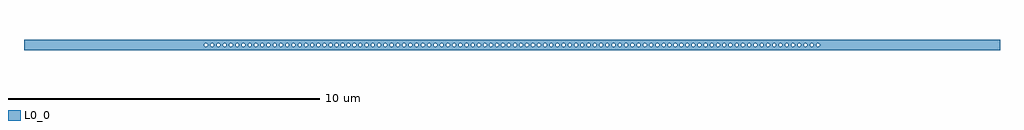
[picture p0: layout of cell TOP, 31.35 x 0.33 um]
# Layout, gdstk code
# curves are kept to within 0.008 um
import gdstk
lib = gdstk.Library(unit=1e-6, precision=1e-09)
def P(c, l, *ps):  # polygons
    for p in ps: c.add(gdstk.Polygon(p, *l))
L0_0 = (0, 0)

top = lib.new_cell('TOP')
P(top, L0_0, [(0,0),(0,0),(0,0),(0,0)],
  [(-8.009,0.053),(-8.009,0.166),(-15.675,0.166),(-15.675,0.055),(-8.027,0.055)],
  [(-8.009,-0.053),(-8.045,-0.051),(-8.077,-0.009),(-8.071,0.026),(-8.027,0.055),(-8.228,0.055),(-8.18,0.034),(-8.168,0),(-8.18,-0.034),(-8.228,-0.055),(-8.26,-0.041),(-8.278,-0.009),(-8.272,0.026),(-8.228,0.055),(-8.429,0.055),(-8.381,0.034),(-8.369,0),(-8.381,-0.034),(-8.429,-0.055),(-8.461,-0.041),(-8.479,-0.009),(-8.473,0.026),(-8.429,0.055),(-8.63,0.055),(-8.582,0.034),(-8.57,0),(-8.582,-0.034),(-8.63,-0.055),(-8.662,-0.041),(-8.68,-0.009),(-8.674,0.026),(-8.63,0.055),(-8.831,0.055),(-8.783,0.034),(-8.771,0),(-8.783,-0.034),(-8.831,-0.055),(-8.863,-0.041),(-8.881,-0.009),(-8.875,0.026),(-8.831,0.055),(-9.032,0.055),(-8.984,0.034),(-8.972,0),(-8.984,-0.034),(-9.032,-0.055),(-9.064,-0.041),(-9.082,-0.009),(-9.076,0.026),(-9.032,0.055),(-9.233,0.055),(-9.185,0.034),(-9.173,0),(-9.185,-0.034),(-9.233,-0.055),(-9.265,-0.041),(-9.283,-0.009),(-9.277,0.026),(-9.233,0.055),(-9.434,0.055),(-9.386,0.034),(-9.374,0),(-9.386,-0.034),(-9.434,-0.055),(-9.466,-0.041),(-9.484,-0.009),(-9.478,0.026),(-9.434,0.055),(-9.635,0.055),(-9.587,0.034),(-9.575,0),(-9.587,-0.034),(-9.635,-0.055),(-9.667,-0.041),(-9.685,-0.009),(-9.679,0.026),(-9.635,0.055),(-9.836,0.055),(-9.788,0.034),(-9.776,0),(-9.788,-0.034),(-9.836,-0.055),(-9.868,-0.041),(-9.886,-0.009),(-9.88,0.026),(-9.836,0.055),(-15.675,0.055),(-15.675,-0.166),(-8.009,-0.166)],
  [(-6.206,0.053),(-6.189,0.046),(-6.176,0.034),(-6.167,0.018),(-6.167,0.166),(-8.009,0.166),(-8.009,0.055),(-6.224,0.055)],
  [(-6.167,-0.018),(-6.189,-0.046),(-6.224,-0.055),(-6.268,-0.026),(-6.268,0.026),(-6.224,0.055),(-6.422,0.055),(-6.375,0.034),(-6.363,0),(-6.375,-0.034),(-6.422,-0.055),(-6.455,-0.041),(-6.472,-0.009),(-6.455,0.041),(-6.422,0.055),(-6.622,0.055),(-6.587,0.046),(-6.562,0),(-6.587,-0.046),(-6.622,-0.055),(-6.654,-0.041),(-6.671,-0.009),(-6.654,0.041),(-6.622,0.055),(-6.822,0.055),(-6.787,0.046),(-6.762,0),(-6.787,-0.046),(-6.822,-0.055),(-6.854,-0.041),(-6.871,-0.009),(-6.866,0.026),(-6.822,0.055),(-7.022,0.055),(-6.975,0.034),(-6.963,0),(-6.975,-0.034),(-7.022,-0.055),(-7.055,-0.041),(-7.072,-0.009),(-7.055,0.041),(-7.022,0.055),(-7.223,0.055),(-7.175,0.034),(-7.164,0),(-7.175,-0.034),(-7.223,-0.055),(-7.256,-0.041),(-7.273,-0.009),(-7.256,0.041),(-7.223,0.055),(-7.424,0.055),(-7.376,0.034),(-7.365,0),(-7.376,-0.034),(-7.424,-0.055),(-7.457,-0.041),(-7.474,-0.009),(-7.457,0.041),(-7.424,0.055),(-7.625,0.055),(-7.577,0.034),(-7.565,0),(-7.577,-0.034),(-7.625,-0.055),(-7.657,-0.041),(-7.675,-0.009),(-7.669,0.026),(-7.625,0.055),(-7.826,0.055),(-7.778,0.034),(-7.766,0),(-7.778,-0.034),(-7.826,-0.055),(-7.858,-0.041),(-7.876,-0.009),(-7.87,0.026),(-7.826,0.055),(-8.009,0.055),(-7.979,0.034),(-7.967,0),(-7.979,-0.034),(-8.009,-0.053),(-8.009,-0.166),(-6.167,-0.166)],
  [(-4.457,0.053),(-4.44,0.046),(-4.427,0.034),(-4.418,0.018),(-4.418,0.166),(-6.167,0.166),(-6.167,0.055),(-4.474,0.055)],
  [(-4.418,-0.018),(-4.457,-0.053),(-4.507,-0.041),(-4.524,0.009),(-4.507,0.041),(-4.474,0.055),(-4.675,0.055),(-4.628,0.034),(-4.616,0),(-4.628,-0.034),(-4.675,-0.055),(-4.708,-0.041),(-4.725,-0.009),(-4.708,0.041),(-4.675,0.055),(-4.876,0.055),(-4.829,0.034),(-4.817,0),(-4.829,-0.034),(-4.876,-0.055),(-4.909,-0.041),(-4.926,-0.009),(-4.909,0.041),(-4.876,0.055),(-5.065,0.055),(-5.018,0.034),(-5.006,0),(-5.018,-0.034),(-5.065,-0.055),(-5.098,-0.041),(-5.115,-0.009),(-5.098,0.041),(-5.065,0.055),(-5.255,0.055),(-5.22,0.046),(-5.195,0),(-5.22,-0.046),(-5.255,-0.055),(-5.287,-0.041),(-5.304,-0.009),(-5.299,0.026),(-5.255,0.055),(-5.445,0.055),(-5.397,0.034),(-5.386,0),(-5.397,-0.034),(-5.445,-0.055),(-5.478,-0.041),(-5.495,-0.009),(-5.478,0.041),(-5.445,0.055),(-5.637,0.055),(-5.589,0.034),(-5.578,0),(-5.589,-0.034),(-5.637,-0.055),(-5.67,-0.041),(-5.687,-0.009),(-5.67,0.041),(-5.637,0.055),(-5.831,0.055),(-5.783,0.034),(-5.772,0),(-5.783,-0.034),(-5.831,-0.055),(-5.864,-0.041),(-5.881,-0.009),(-5.864,0.041),(-5.831,0.055),(-6.027,0.055),(-5.992,0.046),(-5.967,0),(-5.992,-0.046),(-6.027,-0.055),(-6.059,-0.041),(-6.076,-0.009),(-6.059,0.041),(-6.027,0.055),(-6.167,0.055),(-6.167,-0.166),(-4.418,-0.166)],
  [(-2.648,0.053),(-2.631,0.046),(-2.618,0.034),(-2.609,0.018),(-2.609,0.166),(-4.418,0.166),(-4.418,0.055),(-2.665,0.055)],
  [(-2.609,-0.018),(-2.648,-0.053),(-2.698,-0.041),(-2.715,0.009),(-2.698,0.041),(-2.665,0.055),(-2.866,0.055),(-2.819,0.034),(-2.807,0),(-2.819,-0.034),(-2.866,-0.055),(-2.899,-0.041),(-2.916,-0.009),(-2.899,0.041),(-2.866,0.055),(-3.067,0.055),(-3.02,0.034),(-3.008,0),(-3.02,-0.034),(-3.067,-0.055),(-3.1,-0.041),(-3.117,-0.009),(-3.1,0.041),(-3.067,0.055),(-3.268,0.055),(-3.221,0.034),(-3.209,0),(-3.221,-0.034),(-3.268,-0.055),(-3.301,-0.041),(-3.318,-0.009),(-3.301,0.041),(-3.268,0.055),(-3.469,0.055),(-3.422,0.034),(-3.41,0),(-3.422,-0.034),(-3.469,-0.055),(-3.502,-0.041),(-3.519,-0.009),(-3.502,0.041),(-3.469,0.055),(-3.67,0.055),(-3.623,0.034),(-3.611,0),(-3.623,-0.034),(-3.67,-0.055),(-3.703,-0.041),(-3.72,-0.009),(-3.703,0.041),(-3.67,0.055),(-3.871,0.055),(-3.824,0.034),(-3.812,0),(-3.824,-0.034),(-3.871,-0.055),(-3.904,-0.041),(-3.921,-0.009),(-3.904,0.041),(-3.871,0.055),(-4.072,0.055),(-4.025,0.034),(-4.013,0),(-4.025,-0.034),(-4.072,-0.055),(-4.105,-0.041),(-4.122,-0.009),(-4.105,0.041),(-4.072,0.055),(-4.273,0.055),(-4.226,0.034),(-4.214,0),(-4.226,-0.034),(-4.273,-0.055),(-4.306,-0.041),(-4.323,-0.009),(-4.306,0.041),(-4.273,0.055),(-4.418,0.055),(-4.418,-0.166),(-2.609,-0.166)],
  [(-0.854,0.053),(-0.837,0.046),(-0.824,0.034),(-0.815,0.018),(-0.815,0.166),(-2.609,0.166),(-2.609,0.055),(-0.871,0.055)],
  [(-0.815,-0.018),(-0.854,-0.053),(-0.904,-0.041),(-0.921,0.009),(-0.904,0.041),(-0.871,0.055),(-1.067,0.055),(-1.019,0.034),(-1.008,0),(-1.019,-0.034),(-1.067,-0.055),(-1.1,-0.041),(-1.117,-0.009),(-1.1,0.041),(-1.067,0.055),(-1.264,0.055),(-1.217,0.034),(-1.205,0),(-1.217,-0.034),(-1.264,-0.055),(-1.297,-0.041),(-1.314,-0.009),(-1.297,0.041),(-1.264,0.055),(-1.463,0.055),(-1.428,0.046),(-1.403,0),(-1.428,-0.046),(-1.463,-0.055),(-1.495,-0.041),(-1.512,-0.009),(-1.507,0.026),(-1.463,0.055),(-1.662,0.055),(-1.615,0.034),(-1.603,0),(-1.615,-0.034),(-1.662,-0.055),(-1.695,-0.041),(-1.712,-0.009),(-1.695,0.041),(-1.662,0.055),(-1.862,0.055),(-1.815,0.034),(-1.803,0),(-1.815,-0.034),(-1.862,-0.055),(-1.895,-0.041),(-1.912,-0.009),(-1.895,0.041),(-1.862,0.055),(-2.063,0.055),(-2.015,0.034),(-2.003,0),(-2.015,-0.034),(-2.063,-0.055),(-2.095,-0.041),(-2.113,-0.009),(-2.107,0.026),(-2.063,0.055),(-2.264,0.055),(-2.229,0.046),(-2.204,0),(-2.229,-0.046),(-2.264,-0.055),(-2.296,-0.041),(-2.313,-0.009),(-2.296,0.041),(-2.264,0.055),(-2.464,0.055),(-2.417,0.034),(-2.405,0),(-2.417,-0.034),(-2.464,-0.055),(-2.497,-0.041),(-2.514,-0.009),(-2.497,0.041),(-2.464,0.055),(-2.609,0.055),(-2.609,-0.166),(-0.815,-0.166)],
  [(0.881,0.053),(0.897,0.046),(0.91,0.034),(0.919,0.018),(0.919,0.166),(-0.815,0.166),(-0.815,0.055),(0.863,0.055)],
  [(0.919,-0.018),(0.881,-0.053),(0.83,-0.041),(0.813,0.009),(0.83,0.041),(0.863,0.055),(0.669,0.055),(0.717,0.034),(0.728,0),(0.717,-0.034),(0.669,-0.055),(0.636,-0.041),(0.619,-0.009),(0.636,0.041),(0.669,0.055),(0.477,0.055),(0.525,0.034),(0.536,0),(0.525,-0.034),(0.477,-0.055),(0.444,-0.041),(0.427,-0.009),(0.444,0.041),(0.477,0.055),(0.287,0.055),(0.334,0.034),(0.346,0),(0.334,-0.034),(0.287,-0.055),(0.254,-0.041),(0.237,-0.009),(0.254,0.041),(0.287,0.055),(0.097,0.055),(0.145,0.034),(0.157,0),(0.145,-0.034),(0.097,-0.055),(0.064,-0.041),(0.047,-0.009),(0.064,0.041),(0.097,0.055),(-0.106,0.055),(-0.058,0.034),(-0.046,0),(-0.058,-0.034),(-0.106,-0.055),(-0.139,-0.041),(-0.156,-0.009),(-0.139,0.041),(-0.106,0.055),(-0.295,0.055),(-0.248,0.034),(-0.236,0),(-0.248,-0.034),(-0.295,-0.055),(-0.328,-0.041),(-0.345,-0.009),(-0.328,0.041),(-0.295,0.055),(-0.486,0.055),(-0.451,0.046),(-0.426,0),(-0.451,-0.046),(-0.486,-0.055),(-0.518,-0.041),(-0.535,-0.009),(-0.518,0.041),(-0.486,0.055),(-0.678,0.055),(-0.643,0.046),(-0.618,0),(-0.643,-0.046),(-0.678,-0.055),(-0.71,-0.041),(-0.727,-0.009),(-0.71,0.041),(-0.678,0.055),(-0.815,0.055),(-0.815,-0.166),(0.919,-0.166)],
  [(2.674,0.053),(2.691,0.046),(2.691,0.166),(0.919,0.166),(0.919,0.055),(2.657,0.055)],
  [(2.691,-0.046),(2.639,-0.051),(2.607,-0.009),(2.624,0.041),(2.657,0.055),(2.456,0.055),(2.503,0.034),(2.515,0),(2.503,-0.034),(2.456,-0.055),(2.423,-0.041),(2.406,-0.009),(2.423,0.041),(2.456,0.055),(2.255,0.055),(2.302,0.034),(2.314,0),(2.302,-0.034),(2.255,-0.055),(2.222,-0.041),(2.205,-0.009),(2.222,0.041),(2.255,0.055),(2.054,0.055),(2.102,0.034),(2.113,0),(2.102,-0.034),(2.054,-0.055),(2.021,-0.041),(2.004,-0.009),(2.021,0.041),(2.054,0.055),(1.854,0.055),(1.901,0.034),(1.913,0),(1.901,-0.034),(1.854,-0.055),(1.821,-0.041),(1.804,-0.009),(1.821,0.041),(1.854,0.055),(1.653,0.055),(1.688,0.046),(1.713,0),(1.688,-0.046),(1.653,-0.055),(1.621,-0.041),(1.604,-0.009),(1.621,0.041),(1.653,0.055),(1.454,0.055),(1.502,0.034),(1.513,0),(1.502,-0.034),(1.454,-0.055),(1.421,-0.041),(1.404,-0.009),(1.421,0.041),(1.454,0.055),(1.256,0.055),(1.303,0.034),(1.315,0),(1.303,-0.034),(1.256,-0.055),(1.223,-0.041),(1.206,-0.009),(1.223,0.041),(1.256,0.055),(1.058,0.055),(1.093,0.046),(1.118,0),(1.093,-0.046),(1.058,-0.055),(1.026,-0.041),(1.009,-0.009),(1.026,0.041),(1.058,0.055),(0.919,0.055),(0.919,-0.166),(2.691,-0.166)],
  [(4.483,0.053),(4.5,0.046),(4.5,0.166),(2.691,0.166),(2.691,0.055),(4.466,0.055)],
  [(4.5,-0.046),(4.448,-0.051),(4.416,-0.009),(4.433,0.041),(4.466,0.055),(4.265,0.055),(4.312,0.034),(4.324,0),(4.312,-0.034),(4.265,-0.055),(4.232,-0.041),(4.215,-0.009),(4.232,0.041),(4.265,0.055),(4.064,0.055),(4.111,0.034),(4.123,0),(4.111,-0.034),(4.064,-0.055),(4.031,-0.041),(4.014,-0.009),(4.031,0.041),(4.064,0.055),(3.863,0.055),(3.91,0.034),(3.922,0),(3.91,-0.034),(3.863,-0.055),(3.83,-0.041),(3.813,-0.009),(3.83,0.041),(3.863,0.055),(3.662,0.055),(3.709,0.034),(3.721,0),(3.709,-0.034),(3.662,-0.055),(3.629,-0.041),(3.612,-0.009),(3.629,0.041),(3.662,0.055),(3.461,0.055),(3.508,0.034),(3.52,0),(3.508,-0.034),(3.461,-0.055),(3.428,-0.041),(3.411,-0.009),(3.428,0.041),(3.461,0.055),(3.26,0.055),(3.307,0.034),(3.319,0),(3.307,-0.034),(3.26,-0.055),(3.227,-0.041),(3.21,-0.009),(3.227,0.041),(3.26,0.055),(3.059,0.055),(3.106,0.034),(3.118,0),(3.106,-0.034),(3.059,-0.055),(3.026,-0.041),(3.009,-0.009),(3.026,0.041),(3.059,0.055),(2.858,0.055),(2.905,0.034),(2.917,0),(2.905,-0.034),(2.858,-0.055),(2.825,-0.041),(2.808,-0.009),(2.825,0.041),(2.858,0.055),(2.691,0.055),(2.716,0),(2.691,-0.046),(2.691,-0.166),(4.5,-0.166)],
  [(6.233,0.053),(6.249,0.046),(6.249,0.166),(4.5,0.166),(4.5,0.055),(6.215,0.055)],
  [(6.249,-0.046),(6.197,-0.051),(6.165,-0.009),(6.182,0.041),(6.215,0.055),(6.018,0.055),(6.065,0.034),(6.077,0),(6.065,-0.034),(6.018,-0.055),(5.985,-0.041),(5.968,-0.009),(5.985,0.041),(6.018,0.055),(5.822,0.055),(5.87,0.034),(5.882,0),(5.87,-0.034),(5.822,-0.055),(5.79,-0.041),(5.772,-0.009),(5.778,0.026),(5.822,0.055),(5.628,0.055),(5.663,0.046),(5.688,0),(5.663,-0.046),(5.628,-0.055),(5.596,-0.041),(5.579,-0.009),(5.596,0.041),(5.628,0.055),(5.436,0.055),(5.471,0.046),(5.496,0),(5.471,-0.046),(5.436,-0.055),(5.404,-0.041),(5.387,-0.009),(5.404,0.041),(5.436,0.055),(5.246,0.055),(5.294,0.034),(5.305,0),(5.294,-0.034),(5.246,-0.055),(5.213,-0.041),(5.196,-0.009),(5.213,0.041),(5.246,0.055),(5.057,0.055),(5.104,0.034),(5.116,0),(5.104,-0.034),(5.057,-0.055),(5.024,-0.041),(5.007,-0.009),(5.024,0.041),(5.057,0.055),(4.868,0.055),(4.915,0.034),(4.927,0),(4.915,-0.034),(4.868,-0.055),(4.835,-0.041),(4.818,-0.009),(4.835,0.041),(4.868,0.055),(4.667,0.055),(4.714,0.034),(4.726,0),(4.714,-0.034),(4.667,-0.055),(4.634,-0.041),(4.617,-0.009),(4.634,0.041),(4.667,0.055),(4.5,0.055),(4.525,0),(4.5,-0.046),(4.5,-0.166),(6.249,-0.166)],
  [(8.036,0.053),(8.052,0.046),(8.066,0.034),(8.074,0.018),(8.074,0.166),(6.249,0.166),(6.249,0.055),(8.018,0.055)],
  [(8.074,-0.018),(8.036,-0.053),(7.985,-0.041),(7.968,0.009),(7.985,0.041),(8.018,0.055),(7.817,0.055),(7.865,0.034),(7.876,0),(7.865,-0.034),(7.817,-0.055),(7.784,-0.041),(7.767,-0.009),(7.784,0.041),(7.817,0.055),(7.616,0.055),(7.664,0.034),(7.675,0),(7.664,-0.034),(7.616,-0.055),(7.583,-0.041),(7.566,-0.009),(7.583,0.041),(7.616,0.055),(7.415,0.055),(7.463,0.034),(7.475,0),(7.463,-0.034),(7.415,-0.055),(7.382,-0.041),(7.365,-0.009),(7.382,0.041),(7.415,0.055),(7.214,0.055),(7.249,0.046),(7.274,0),(7.249,-0.046),(7.214,-0.055),(7.182,-0.041),(7.165,-0.009),(7.17,0.026),(7.214,0.055),(7.014,0.055),(7.061,0.034),(7.073,0),(7.061,-0.034),(7.014,-0.055),(6.981,-0.041),(6.964,-0.009),(6.981,0.041),(7.014,0.055),(6.813,0.055),(6.861,0.034),(6.872,0),(6.861,-0.034),(6.813,-0.055),(6.78,-0.041),(6.763,-0.009),(6.78,0.041),(6.813,0.055),(6.613,0.055),(6.661,0.034),(6.672,0),(6.661,-0.034),(6.613,-0.055),(6.58,-0.041),(6.563,-0.009),(6.58,0.041),(6.613,0.055),(6.413,0.055),(6.448,0.046),(6.473,0),(6.448,-0.046),(6.413,-0.055),(6.381,-0.041),(6.364,-0.009),(6.381,0.041),(6.413,0.055),(6.249,0.055),(6.274,0),(6.249,-0.046),(6.249,-0.166),(8.074,-0.166)],
  [(8.077,0),(8.075,-0.009),(8.169,-0.009),(8.186,0.041),(8.219,0.055),(8.267,0.034),(8.276,-0.009),(8.37,-0.009),(8.387,0.041),(8.42,0.055),(8.468,0.034),(8.477,-0.009),(8.571,-0.009),(8.588,0.041),(8.621,0.055),(8.669,0.034),(8.678,-0.009),(8.772,-0.009),(8.789,0.041),(8.84,0.053),(8.87,0.034),(8.881,0),(8.87,-0.034),(8.822,-0.055),(8.789,-0.041),(8.772,-0.009),(8.678,-0.009),(8.655,-0.046),(8.621,-0.055),(8.588,-0.041),(8.571,-0.009),(8.477,-0.009),(8.454,-0.046),(8.42,-0.055),(8.387,-0.041),(8.37,-0.009),(8.276,-0.009),(8.253,-0.046),(8.219,-0.055),(8.186,-0.041),(8.169,-0.009),(8.075,-0.009),(8.074,-0.166),(9.023,-0.166),(9.023,-0.055),(8.99,-0.041),(8.973,-0.009),(8.99,0.041),(9.023,0.055),(9.023,0.166),(8.074,0.166)],
  [(9.071,-0.034),(9.023,-0.055),(9.023,-0.166),(15.675,-0.166),(15.675,0.166),(9.023,0.166),(9.023,0.055),(9.071,0.034),(9.08,-0.009),(9.174,-0.009),(9.191,0.041),(9.224,0.055),(9.272,0.034),(9.281,-0.009),(9.375,-0.009),(9.392,0.041),(9.425,0.055),(9.473,0.034),(9.482,-0.009),(9.576,-0.009),(9.593,0.041),(9.626,0.055),(9.674,0.034),(9.683,-0.009),(9.777,-0.009),(9.794,0.041),(9.827,0.055),(9.861,0.046),(9.883,0.018),(9.875,-0.034),(9.827,-0.055),(9.794,-0.041),(9.777,-0.009),(9.683,-0.009),(9.66,-0.046),(9.626,-0.055),(9.593,-0.041),(9.576,-0.009),(9.482,-0.009),(9.459,-0.046),(9.425,-0.055),(9.392,-0.041),(9.375,-0.009),(9.281,-0.009),(9.258,-0.046),(9.224,-0.055),(9.191,-0.041),(9.174,-0.009),(9.08,-0.009)])

lib.write_gds('TOP.gds')
